VERSION 5.7 ;
  NOWIREEXTENSIONATPIN ON ;
  DIVIDERCHAR "/" ;
  BUSBITCHARS "[]" ;
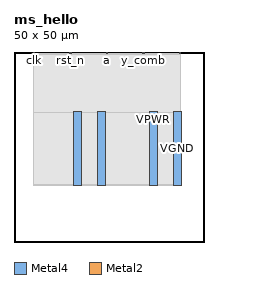
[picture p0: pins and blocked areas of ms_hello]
MACRO ms_hello
  CLASS BLOCK ;
  FOREIGN ms_hello ;
  ORIGIN 0.000 0.000 ;
  SIZE 50.000 BY 50.000 ;
  PIN VGND
    DIRECTION INOUT ;
    USE GROUND ;
    PORT
      LAYER Metal4 ;
        RECT 21.860 14.900 24.060 34.240 ;
    END
    PORT
      LAYER Metal4 ;
        RECT 41.860 14.900 44.060 34.240 ;
    END
  END VGND
  PIN VPWR
    DIRECTION INOUT ;
    USE POWER ;
    PORT
      LAYER Metal4 ;
        RECT 15.660 14.900 17.860 34.240 ;
    END
    PORT
      LAYER Metal4 ;
        RECT 35.660 14.900 37.860 34.240 ;
    END
  END VPWR
  PIN a
    DIRECTION INPUT ;
    USE SIGNAL ;
    ANTENNAGATEAREA 0.180700 ;
    PORT
      LAYER Metal2 ;
        RECT 24.280 49.600 24.680 50.000 ;
    END
  END a
  PIN clk
    DIRECTION INPUT ;
    USE SIGNAL ;
    ANTENNAGATEAREA 0.241800 ;
    PORT
      LAYER Metal2 ;
        RECT 5.080 49.600 5.480 50.000 ;
    END
  END clk
  PIN rst_n
    DIRECTION INPUT ;
    USE SIGNAL ;
    ANTENNAGATEAREA 0.180700 ;
    PORT
      LAYER Metal2 ;
        RECT 14.680 49.600 15.080 50.000 ;
    END
  END rst_n
  PIN y_comb
    DIRECTION OUTPUT ;
    USE SIGNAL ;
    ANTENNADIFFAREA 0.708600 ;
    PORT
      LAYER Metal2 ;
        RECT 33.880 49.600 34.280 50.000 ;
    END
  END y_comb
  PIN y_reg
    DIRECTION OUTPUT ;
    USE SIGNAL ;
    ANTENNADIFFAREA 0.708600 ;
    PORT
      LAYER Metal2 ;
        RECT 43.480 49.600 43.880 50.000 ;
    END
  END y_reg
  OBS
      LAYER GatPoly ;
        RECT 5.760 14.970 44.160 34.170 ;
      LAYER Metal1 ;
        RECT 5.760 14.900 44.160 34.240 ;
      LAYER Metal2 ;
        RECT 5.690 49.390 14.470 49.600 ;
        RECT 15.290 49.390 24.070 49.600 ;
        RECT 24.890 49.390 33.670 49.600 ;
        RECT 34.490 49.390 43.270 49.600 ;
        RECT 5.175 14.975 43.880 49.390 ;
      LAYER Metal3 ;
        RECT 5.135 15.020 43.925 34.120 ;
  END
END ms_hello
END LIBRARY

